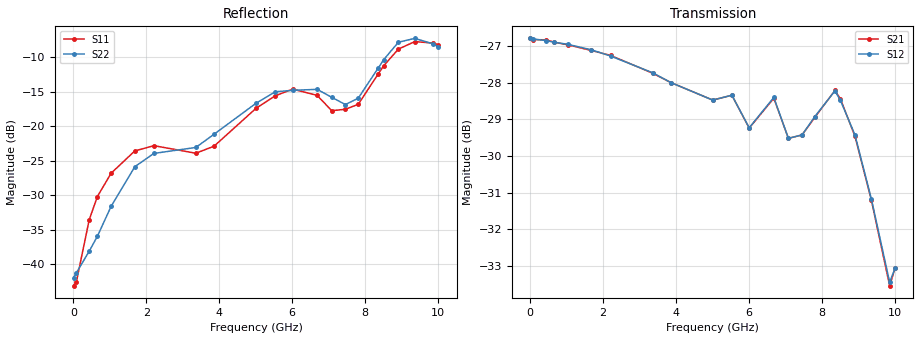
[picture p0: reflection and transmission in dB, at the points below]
! Device ID: PE43705
! Serial: 1
! Insertion: A
! Impedance: 50 ohm
! Temp: 25C
! VDD: 3.400V
! Attenuation Step: 25.75dB
#  Hz  S  RI  R  50
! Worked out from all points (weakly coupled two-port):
!   401 points, 10 MHz to 10.01 GHz, reference 50 ohm
!   highest |S21| = -26.79 dB at 10 MHz (marker M1); lowest = -33.5 dB at 9.86 GHz (marker M2)
!   lowest |S11| = -43.1 dB at 10 MHz (marker M3), VSWR 1.01, Z = 49.3 + j0.0452 ohm
!   |S11| at or under -10 dB: start of sweep to 8.689 GHz
!   |S22| runs from -41.9 to -7.3 dB; largest |S21 - S12| = 0.00069
!   S11 on the Smith chart (normalised r, x): 10 MHz: 0.99, +0.00; 7.46 GHz: 0.82, +0.16; 8.51 GHz: 0.82, +0.48; 9.36 GHz: 0.54, +0.48; 10.01 GHz: 0.48, +0.26
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1e7  -0.00699 0.000458  0.0458 -0.000235  0.0458 -0.000171  0.00801 0.000307
8.5e7  -0.00662 0.00348  0.0456 -0.00108  0.0457 -0.00107  0.00837 0.00237
4.35e8  -0.0117 0.0174  0.0453 -0.0052  0.0452 -0.00508  0.00321 0.012
6.6e8  -0.0199 0.0237  0.0446 -0.00766  0.0446 -0.00759  -0.00458 0.0153
1.035e9  -0.037 0.0266  0.0433 -0.0118  0.0434 -0.0117  -0.0218 0.0146
1.685e9  -0.0641 0.0164  0.0402 -0.0181  0.0403 -0.0181  -0.0508 0.00215
2.21e9  -0.0722 0.00163  0.037 -0.0227  0.0369 -0.0227  -0.0627 -0.0101
3.36e9  -0.0636 0.00317  0.0278 -0.0302  0.028 -0.0301  -0.0701 -0.00152
3.86e9  -0.0668 0.0259  0.0239 -0.0319  0.0239 -0.0319  -0.0857 0.0175
5.01e9  -0.1035 0.0862  0.0159 -0.0342  0.0159 -0.0342  -0.128 0.0712
5.535e9  -0.133 0.0989  0.0119 -0.0364  0.0119 -0.0364  -0.1501 0.0942
6.01e9  -0.1561 0.0999  0.00838 -0.0335  0.00852 -0.0335  -0.1503 0.102
6.685e9  -0.1469 0.0794  0.00504 -0.0376  0.005 -0.0377  -0.1511 0.1061
7.085e9  -0.1138 0.0615  -0.00152 -0.0334  -0.00156 -0.0334  -0.1139 0.1148
7.46e9  -0.0929 0.0945  -0.000341 -0.0338  -0.000275 -0.0338  -0.0717 0.1241
7.81e9  -0.0489 0.1352  -0.0011 -0.0357  -0.000928 -0.0358  -0.041 0.1538
8.36e9  -0.0165 0.2381  -0.0106 -0.0374  -0.0104 -0.0374  -0.0187 0.2628
8.51e9  -0.0255 0.2725  -0.0137 -0.0353  -0.0135 -0.0352  -0.0237 0.3019
8.91e9  -0.08 0.3518  -0.0174 -0.0288  -0.0175 -0.0289  -0.076 0.3972
9.36e9  -0.1807 0.3669  -0.0164 -0.0221  -0.0163 -0.0223  -0.1587 0.4016
9.86e9  -0.2891 0.2759  -0.00787 -0.0195  -0.00801 -0.0197  -0.2687 0.2882
1.001e10  -0.3143 0.2281  -0.00518 -0.0216  -0.00517 -0.0216  -0.2965 0.2282
